# Generated by innovus_enablement/scripts/gen_fakeram.py: abstract 32x64 SRAM.
# Geometry is an assumption (see script header), not PDK data.
VERSION 5.8 ;
BUSBITCHARS "[]" ;
DIVIDERCHAR "/" ;

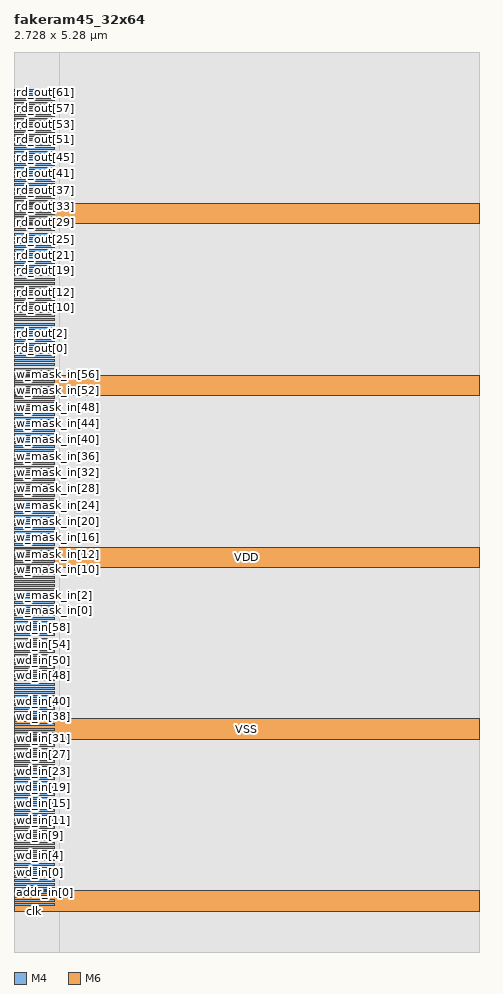
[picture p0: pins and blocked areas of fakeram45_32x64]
MACRO fakeram45_32x64
  CLASS BLOCK ;
  FOREIGN fakeram45_32x64 0 0 ;
  ORIGIN 0 0 ;
  SIZE 2.7280 BY 5.2800 ;
  SYMMETRY X Y R90 ;
  PIN clk
    DIRECTION INPUT ;
    USE CLOCK ;
    PORT
      LAYER M4 ;
        RECT 0 0.2700 0.2400 0.2820 ;
    END
  END clk
  PIN ce_in
    DIRECTION INPUT ;
    USE SIGNAL ;
    PORT
      LAYER M4 ;
        RECT 0 0.2940 0.2400 0.3060 ;
    END
  END ce_in
  PIN we_in
    DIRECTION INPUT ;
    USE SIGNAL ;
    PORT
      LAYER M4 ;
        RECT 0 0.3180 0.2400 0.3300 ;
    END
  END we_in
  PIN addr_in[0]
    DIRECTION INPUT ;
    USE SIGNAL ;
    PORT
      LAYER M4 ;
        RECT 0 0.3420 0.2400 0.3540 ;
    END
  END addr_in[0]
  PIN addr_in[1]
    DIRECTION INPUT ;
    USE SIGNAL ;
    PORT
      LAYER M4 ;
        RECT 0 0.3660 0.2400 0.3780 ;
    END
  END addr_in[1]
  PIN addr_in[2]
    DIRECTION INPUT ;
    USE SIGNAL ;
    PORT
      LAYER M4 ;
        RECT 0 0.3900 0.2400 0.4020 ;
    END
  END addr_in[2]
  PIN addr_in[3]
    DIRECTION INPUT ;
    USE SIGNAL ;
    PORT
      LAYER M4 ;
        RECT 0 0.4140 0.2400 0.4260 ;
    END
  END addr_in[3]
  PIN addr_in[4]
    DIRECTION INPUT ;
    USE SIGNAL ;
    PORT
      LAYER M4 ;
        RECT 0 0.4380 0.2400 0.4500 ;
    END
  END addr_in[4]
  PIN wd_in[0]
    DIRECTION INPUT ;
    USE SIGNAL ;
    PORT
      LAYER M4 ;
        RECT 0 0.4620 0.2400 0.4740 ;
    END
  END wd_in[0]
  PIN wd_in[1]
    DIRECTION INPUT ;
    USE SIGNAL ;
    PORT
      LAYER M4 ;
        RECT 0 0.4860 0.2400 0.4980 ;
    END
  END wd_in[1]
  PIN wd_in[2]
    DIRECTION INPUT ;
    USE SIGNAL ;
    PORT
      LAYER M4 ;
        RECT 0 0.5100 0.2400 0.5220 ;
    END
  END wd_in[2]
  PIN wd_in[3]
    DIRECTION INPUT ;
    USE SIGNAL ;
    PORT
      LAYER M4 ;
        RECT 0 0.5340 0.2400 0.5460 ;
    END
  END wd_in[3]
  PIN wd_in[4]
    DIRECTION INPUT ;
    USE SIGNAL ;
    PORT
      LAYER M4 ;
        RECT 0 0.5580 0.2400 0.5700 ;
    END
  END wd_in[4]
  PIN wd_in[5]
    DIRECTION INPUT ;
    USE SIGNAL ;
    PORT
      LAYER M4 ;
        RECT 0 0.5820 0.2400 0.5940 ;
    END
  END wd_in[5]
  PIN wd_in[6]
    DIRECTION INPUT ;
    USE SIGNAL ;
    PORT
      LAYER M4 ;
        RECT 0 0.6060 0.2400 0.6180 ;
    END
  END wd_in[6]
  PIN wd_in[7]
    DIRECTION INPUT ;
    USE SIGNAL ;
    PORT
      LAYER M4 ;
        RECT 0 0.6300 0.2400 0.6420 ;
    END
  END wd_in[7]
  PIN wd_in[8]
    DIRECTION INPUT ;
    USE SIGNAL ;
    PORT
      LAYER M4 ;
        RECT 0 0.6540 0.2400 0.6660 ;
    END
  END wd_in[8]
  PIN wd_in[9]
    DIRECTION INPUT ;
    USE SIGNAL ;
    PORT
      LAYER M4 ;
        RECT 0 0.6780 0.2400 0.6900 ;
    END
  END wd_in[9]
  PIN wd_in[10]
    DIRECTION INPUT ;
    USE SIGNAL ;
    PORT
      LAYER M4 ;
        RECT 0 0.7020 0.2400 0.7140 ;
    END
  END wd_in[10]
  PIN wd_in[11]
    DIRECTION INPUT ;
    USE SIGNAL ;
    PORT
      LAYER M4 ;
        RECT 0 0.7260 0.2400 0.7380 ;
    END
  END wd_in[11]
  PIN wd_in[12]
    DIRECTION INPUT ;
    USE SIGNAL ;
    PORT
      LAYER M4 ;
        RECT 0 0.7500 0.2400 0.7620 ;
    END
  END wd_in[12]
  PIN wd_in[13]
    DIRECTION INPUT ;
    USE SIGNAL ;
    PORT
      LAYER M4 ;
        RECT 0 0.7740 0.2400 0.7860 ;
    END
  END wd_in[13]
  PIN wd_in[14]
    DIRECTION INPUT ;
    USE SIGNAL ;
    PORT
      LAYER M4 ;
        RECT 0 0.7980 0.2400 0.8100 ;
    END
  END wd_in[14]
  PIN wd_in[15]
    DIRECTION INPUT ;
    USE SIGNAL ;
    PORT
      LAYER M4 ;
        RECT 0 0.8220 0.2400 0.8340 ;
    END
  END wd_in[15]
  PIN wd_in[16]
    DIRECTION INPUT ;
    USE SIGNAL ;
    PORT
      LAYER M4 ;
        RECT 0 0.8460 0.2400 0.8580 ;
    END
  END wd_in[16]
  PIN wd_in[17]
    DIRECTION INPUT ;
    USE SIGNAL ;
    PORT
      LAYER M4 ;
        RECT 0 0.8700 0.2400 0.8820 ;
    END
  END wd_in[17]
  PIN wd_in[18]
    DIRECTION INPUT ;
    USE SIGNAL ;
    PORT
      LAYER M4 ;
        RECT 0 0.8940 0.2400 0.9060 ;
    END
  END wd_in[18]
  PIN wd_in[19]
    DIRECTION INPUT ;
    USE SIGNAL ;
    PORT
      LAYER M4 ;
        RECT 0 0.9180 0.2400 0.9300 ;
    END
  END wd_in[19]
  PIN wd_in[20]
    DIRECTION INPUT ;
    USE SIGNAL ;
    PORT
      LAYER M4 ;
        RECT 0 0.9420 0.2400 0.9540 ;
    END
  END wd_in[20]
  PIN wd_in[21]
    DIRECTION INPUT ;
    USE SIGNAL ;
    PORT
      LAYER M4 ;
        RECT 0 0.9660 0.2400 0.9780 ;
    END
  END wd_in[21]
  PIN wd_in[22]
    DIRECTION INPUT ;
    USE SIGNAL ;
    PORT
      LAYER M4 ;
        RECT 0 0.9900 0.2400 1.0020 ;
    END
  END wd_in[22]
  PIN wd_in[23]
    DIRECTION INPUT ;
    USE SIGNAL ;
    PORT
      LAYER M4 ;
        RECT 0 1.0140 0.2400 1.0260 ;
    END
  END wd_in[23]
  PIN wd_in[24]
    DIRECTION INPUT ;
    USE SIGNAL ;
    PORT
      LAYER M4 ;
        RECT 0 1.0380 0.2400 1.0500 ;
    END
  END wd_in[24]
  PIN wd_in[25]
    DIRECTION INPUT ;
    USE SIGNAL ;
    PORT
      LAYER M4 ;
        RECT 0 1.0620 0.2400 1.0740 ;
    END
  END wd_in[25]
  PIN wd_in[26]
    DIRECTION INPUT ;
    USE SIGNAL ;
    PORT
      LAYER M4 ;
        RECT 0 1.0860 0.2400 1.0980 ;
    END
  END wd_in[26]
  PIN wd_in[27]
    DIRECTION INPUT ;
    USE SIGNAL ;
    PORT
      LAYER M4 ;
        RECT 0 1.1100 0.2400 1.1220 ;
    END
  END wd_in[27]
  PIN wd_in[28]
    DIRECTION INPUT ;
    USE SIGNAL ;
    PORT
      LAYER M4 ;
        RECT 0 1.1340 0.2400 1.1460 ;
    END
  END wd_in[28]
  PIN wd_in[29]
    DIRECTION INPUT ;
    USE SIGNAL ;
    PORT
      LAYER M4 ;
        RECT 0 1.1580 0.2400 1.1700 ;
    END
  END wd_in[29]
  PIN wd_in[30]
    DIRECTION INPUT ;
    USE SIGNAL ;
    PORT
      LAYER M4 ;
        RECT 0 1.1820 0.2400 1.1940 ;
    END
  END wd_in[30]
  PIN wd_in[31]
    DIRECTION INPUT ;
    USE SIGNAL ;
    PORT
      LAYER M4 ;
        RECT 0 1.2060 0.2400 1.2180 ;
    END
  END wd_in[31]
  PIN wd_in[32]
    DIRECTION INPUT ;
    USE SIGNAL ;
    PORT
      LAYER M4 ;
        RECT 0 1.2300 0.2400 1.2420 ;
    END
  END wd_in[32]
  PIN wd_in[33]
    DIRECTION INPUT ;
    USE SIGNAL ;
    PORT
      LAYER M4 ;
        RECT 0 1.2540 0.2400 1.2660 ;
    END
  END wd_in[33]
  PIN wd_in[34]
    DIRECTION INPUT ;
    USE SIGNAL ;
    PORT
      LAYER M4 ;
        RECT 0 1.2780 0.2400 1.2900 ;
    END
  END wd_in[34]
  PIN wd_in[35]
    DIRECTION INPUT ;
    USE SIGNAL ;
    PORT
      LAYER M4 ;
        RECT 0 1.3020 0.2400 1.3140 ;
    END
  END wd_in[35]
  PIN wd_in[36]
    DIRECTION INPUT ;
    USE SIGNAL ;
    PORT
      LAYER M4 ;
        RECT 0 1.3260 0.2400 1.3380 ;
    END
  END wd_in[36]
  PIN wd_in[37]
    DIRECTION INPUT ;
    USE SIGNAL ;
    PORT
      LAYER M4 ;
        RECT 0 1.3500 0.2400 1.3620 ;
    END
  END wd_in[37]
  PIN wd_in[38]
    DIRECTION INPUT ;
    USE SIGNAL ;
    PORT
      LAYER M4 ;
        RECT 0 1.3740 0.2400 1.3860 ;
    END
  END wd_in[38]
  PIN wd_in[39]
    DIRECTION INPUT ;
    USE SIGNAL ;
    PORT
      LAYER M4 ;
        RECT 0 1.3980 0.2400 1.4100 ;
    END
  END wd_in[39]
  PIN wd_in[40]
    DIRECTION INPUT ;
    USE SIGNAL ;
    PORT
      LAYER M4 ;
        RECT 0 1.4220 0.2400 1.4340 ;
    END
  END wd_in[40]
  PIN wd_in[41]
    DIRECTION INPUT ;
    USE SIGNAL ;
    PORT
      LAYER M4 ;
        RECT 0 1.4460 0.2400 1.4580 ;
    END
  END wd_in[41]
  PIN wd_in[42]
    DIRECTION INPUT ;
    USE SIGNAL ;
    PORT
      LAYER M4 ;
        RECT 0 1.4700 0.2400 1.4820 ;
    END
  END wd_in[42]
  PIN wd_in[43]
    DIRECTION INPUT ;
    USE SIGNAL ;
    PORT
      LAYER M4 ;
        RECT 0 1.4940 0.2400 1.5060 ;
    END
  END wd_in[43]
  PIN wd_in[44]
    DIRECTION INPUT ;
    USE SIGNAL ;
    PORT
      LAYER M4 ;
        RECT 0 1.5180 0.2400 1.5300 ;
    END
  END wd_in[44]
  PIN wd_in[45]
    DIRECTION INPUT ;
    USE SIGNAL ;
    PORT
      LAYER M4 ;
        RECT 0 1.5420 0.2400 1.5540 ;
    END
  END wd_in[45]
  PIN wd_in[46]
    DIRECTION INPUT ;
    USE SIGNAL ;
    PORT
      LAYER M4 ;
        RECT 0 1.5660 0.2400 1.5780 ;
    END
  END wd_in[46]
  PIN wd_in[47]
    DIRECTION INPUT ;
    USE SIGNAL ;
    PORT
      LAYER M4 ;
        RECT 0 1.5900 0.2400 1.6020 ;
    END
  END wd_in[47]
  PIN wd_in[48]
    DIRECTION INPUT ;
    USE SIGNAL ;
    PORT
      LAYER M4 ;
        RECT 0 1.6140 0.2400 1.6260 ;
    END
  END wd_in[48]
  PIN wd_in[49]
    DIRECTION INPUT ;
    USE SIGNAL ;
    PORT
      LAYER M4 ;
        RECT 0 1.6380 0.2400 1.6500 ;
    END
  END wd_in[49]
  PIN wd_in[50]
    DIRECTION INPUT ;
    USE SIGNAL ;
    PORT
      LAYER M4 ;
        RECT 0 1.6620 0.2400 1.6740 ;
    END
  END wd_in[50]
  PIN wd_in[51]
    DIRECTION INPUT ;
    USE SIGNAL ;
    PORT
      LAYER M4 ;
        RECT 0 1.6860 0.2400 1.6980 ;
    END
  END wd_in[51]
  PIN wd_in[52]
    DIRECTION INPUT ;
    USE SIGNAL ;
    PORT
      LAYER M4 ;
        RECT 0 1.7100 0.2400 1.7220 ;
    END
  END wd_in[52]
  PIN wd_in[53]
    DIRECTION INPUT ;
    USE SIGNAL ;
    PORT
      LAYER M4 ;
        RECT 0 1.7340 0.2400 1.7460 ;
    END
  END wd_in[53]
  PIN wd_in[54]
    DIRECTION INPUT ;
    USE SIGNAL ;
    PORT
      LAYER M4 ;
        RECT 0 1.7580 0.2400 1.7700 ;
    END
  END wd_in[54]
  PIN wd_in[55]
    DIRECTION INPUT ;
    USE SIGNAL ;
    PORT
      LAYER M4 ;
        RECT 0 1.7820 0.2400 1.7940 ;
    END
  END wd_in[55]
  PIN wd_in[56]
    DIRECTION INPUT ;
    USE SIGNAL ;
    PORT
      LAYER M4 ;
        RECT 0 1.8060 0.2400 1.8180 ;
    END
  END wd_in[56]
  PIN wd_in[57]
    DIRECTION INPUT ;
    USE SIGNAL ;
    PORT
      LAYER M4 ;
        RECT 0 1.8300 0.2400 1.8420 ;
    END
  END wd_in[57]
  PIN wd_in[58]
    DIRECTION INPUT ;
    USE SIGNAL ;
    PORT
      LAYER M4 ;
        RECT 0 1.8540 0.2400 1.8660 ;
    END
  END wd_in[58]
  PIN wd_in[59]
    DIRECTION INPUT ;
    USE SIGNAL ;
    PORT
      LAYER M4 ;
        RECT 0 1.8780 0.2400 1.8900 ;
    END
  END wd_in[59]
  PIN wd_in[60]
    DIRECTION INPUT ;
    USE SIGNAL ;
    PORT
      LAYER M4 ;
        RECT 0 1.9020 0.2400 1.9140 ;
    END
  END wd_in[60]
  PIN wd_in[61]
    DIRECTION INPUT ;
    USE SIGNAL ;
    PORT
      LAYER M4 ;
        RECT 0 1.9260 0.2400 1.9380 ;
    END
  END wd_in[61]
  PIN wd_in[62]
    DIRECTION INPUT ;
    USE SIGNAL ;
    PORT
      LAYER M4 ;
        RECT 0 1.9500 0.2400 1.9620 ;
    END
  END wd_in[62]
  PIN wd_in[63]
    DIRECTION INPUT ;
    USE SIGNAL ;
    PORT
      LAYER M4 ;
        RECT 0 1.9740 0.2400 1.9860 ;
    END
  END wd_in[63]
  PIN w_mask_in[0]
    DIRECTION INPUT ;
    USE SIGNAL ;
    PORT
      LAYER M4 ;
        RECT 0 1.9980 0.2400 2.0100 ;
    END
  END w_mask_in[0]
  PIN w_mask_in[1]
    DIRECTION INPUT ;
    USE SIGNAL ;
    PORT
      LAYER M4 ;
        RECT 0 2.0220 0.2400 2.0340 ;
    END
  END w_mask_in[1]
  PIN w_mask_in[2]
    DIRECTION INPUT ;
    USE SIGNAL ;
    PORT
      LAYER M4 ;
        RECT 0 2.0460 0.2400 2.0580 ;
    END
  END w_mask_in[2]
  PIN w_mask_in[3]
    DIRECTION INPUT ;
    USE SIGNAL ;
    PORT
      LAYER M4 ;
        RECT 0 2.0700 0.2400 2.0820 ;
    END
  END w_mask_in[3]
  PIN w_mask_in[4]
    DIRECTION INPUT ;
    USE SIGNAL ;
    PORT
      LAYER M4 ;
        RECT 0 2.0940 0.2400 2.1060 ;
    END
  END w_mask_in[4]
  PIN w_mask_in[5]
    DIRECTION INPUT ;
    USE SIGNAL ;
    PORT
      LAYER M4 ;
        RECT 0 2.1180 0.2400 2.1300 ;
    END
  END w_mask_in[5]
  PIN w_mask_in[6]
    DIRECTION INPUT ;
    USE SIGNAL ;
    PORT
      LAYER M4 ;
        RECT 0 2.1420 0.2400 2.1540 ;
    END
  END w_mask_in[6]
  PIN w_mask_in[7]
    DIRECTION INPUT ;
    USE SIGNAL ;
    PORT
      LAYER M4 ;
        RECT 0 2.1660 0.2400 2.1780 ;
    END
  END w_mask_in[7]
  PIN w_mask_in[8]
    DIRECTION INPUT ;
    USE SIGNAL ;
    PORT
      LAYER M4 ;
        RECT 0 2.1900 0.2400 2.2020 ;
    END
  END w_mask_in[8]
  PIN w_mask_in[9]
    DIRECTION INPUT ;
    USE SIGNAL ;
    PORT
      LAYER M4 ;
        RECT 0 2.2140 0.2400 2.2260 ;
    END
  END w_mask_in[9]
  PIN w_mask_in[10]
    DIRECTION INPUT ;
    USE SIGNAL ;
    PORT
      LAYER M4 ;
        RECT 0 2.2380 0.2400 2.2500 ;
    END
  END w_mask_in[10]
  PIN w_mask_in[11]
    DIRECTION INPUT ;
    USE SIGNAL ;
    PORT
      LAYER M4 ;
        RECT 0 2.2620 0.2400 2.2740 ;
    END
  END w_mask_in[11]
  PIN w_mask_in[12]
    DIRECTION INPUT ;
    USE SIGNAL ;
    PORT
      LAYER M4 ;
        RECT 0 2.2860 0.2400 2.2980 ;
    END
  END w_mask_in[12]
  PIN w_mask_in[13]
    DIRECTION INPUT ;
    USE SIGNAL ;
    PORT
      LAYER M4 ;
        RECT 0 2.3100 0.2400 2.3220 ;
    END
  END w_mask_in[13]
  PIN w_mask_in[14]
    DIRECTION INPUT ;
    USE SIGNAL ;
    PORT
      LAYER M4 ;
        RECT 0 2.3340 0.2400 2.3460 ;
    END
  END w_mask_in[14]
  PIN w_mask_in[15]
    DIRECTION INPUT ;
    USE SIGNAL ;
    PORT
      LAYER M4 ;
        RECT 0 2.3580 0.2400 2.3700 ;
    END
  END w_mask_in[15]
  PIN w_mask_in[16]
    DIRECTION INPUT ;
    USE SIGNAL ;
    PORT
      LAYER M4 ;
        RECT 0 2.3820 0.2400 2.3940 ;
    END
  END w_mask_in[16]
  PIN w_mask_in[17]
    DIRECTION INPUT ;
    USE SIGNAL ;
    PORT
      LAYER M4 ;
        RECT 0 2.4060 0.2400 2.4180 ;
    END
  END w_mask_in[17]
  PIN w_mask_in[18]
    DIRECTION INPUT ;
    USE SIGNAL ;
    PORT
      LAYER M4 ;
        RECT 0 2.4300 0.2400 2.4420 ;
    END
  END w_mask_in[18]
  PIN w_mask_in[19]
    DIRECTION INPUT ;
    USE SIGNAL ;
    PORT
      LAYER M4 ;
        RECT 0 2.4540 0.2400 2.4660 ;
    END
  END w_mask_in[19]
  PIN w_mask_in[20]
    DIRECTION INPUT ;
    USE SIGNAL ;
    PORT
      LAYER M4 ;
        RECT 0 2.4780 0.2400 2.4900 ;
    END
  END w_mask_in[20]
  PIN w_mask_in[21]
    DIRECTION INPUT ;
    USE SIGNAL ;
    PORT
      LAYER M4 ;
        RECT 0 2.5020 0.2400 2.5140 ;
    END
  END w_mask_in[21]
  PIN w_mask_in[22]
    DIRECTION INPUT ;
    USE SIGNAL ;
    PORT
      LAYER M4 ;
        RECT 0 2.5260 0.2400 2.5380 ;
    END
  END w_mask_in[22]
  PIN w_mask_in[23]
    DIRECTION INPUT ;
    USE SIGNAL ;
    PORT
      LAYER M4 ;
        RECT 0 2.5500 0.2400 2.5620 ;
    END
  END w_mask_in[23]
  PIN w_mask_in[24]
    DIRECTION INPUT ;
    USE SIGNAL ;
    PORT
      LAYER M4 ;
        RECT 0 2.5740 0.2400 2.5860 ;
    END
  END w_mask_in[24]
  PIN w_mask_in[25]
    DIRECTION INPUT ;
    USE SIGNAL ;
    PORT
      LAYER M4 ;
        RECT 0 2.5980 0.2400 2.6100 ;
    END
  END w_mask_in[25]
  PIN w_mask_in[26]
    DIRECTION INPUT ;
    USE SIGNAL ;
    PORT
      LAYER M4 ;
        RECT 0 2.6220 0.2400 2.6340 ;
    END
  END w_mask_in[26]
  PIN w_mask_in[27]
    DIRECTION INPUT ;
    USE SIGNAL ;
    PORT
      LAYER M4 ;
        RECT 0 2.6460 0.2400 2.6580 ;
    END
  END w_mask_in[27]
  PIN w_mask_in[28]
    DIRECTION INPUT ;
    USE SIGNAL ;
    PORT
      LAYER M4 ;
        RECT 0 2.6700 0.2400 2.6820 ;
    END
  END w_mask_in[28]
  PIN w_mask_in[29]
    DIRECTION INPUT ;
    USE SIGNAL ;
    PORT
      LAYER M4 ;
        RECT 0 2.6940 0.2400 2.7060 ;
    END
  END w_mask_in[29]
  PIN w_mask_in[30]
    DIRECTION INPUT ;
    USE SIGNAL ;
    PORT
      LAYER M4 ;
        RECT 0 2.7180 0.2400 2.7300 ;
    END
  END w_mask_in[30]
  PIN w_mask_in[31]
    DIRECTION INPUT ;
    USE SIGNAL ;
    PORT
      LAYER M4 ;
        RECT 0 2.7420 0.2400 2.7540 ;
    END
  END w_mask_in[31]
  PIN w_mask_in[32]
    DIRECTION INPUT ;
    USE SIGNAL ;
    PORT
      LAYER M4 ;
        RECT 0 2.7660 0.2400 2.7780 ;
    END
  END w_mask_in[32]
  PIN w_mask_in[33]
    DIRECTION INPUT ;
    USE SIGNAL ;
    PORT
      LAYER M4 ;
        RECT 0 2.7900 0.2400 2.8020 ;
    END
  END w_mask_in[33]
  PIN w_mask_in[34]
    DIRECTION INPUT ;
    USE SIGNAL ;
    PORT
      LAYER M4 ;
        RECT 0 2.8140 0.2400 2.8260 ;
    END
  END w_mask_in[34]
  PIN w_mask_in[35]
    DIRECTION INPUT ;
    USE SIGNAL ;
    PORT
      LAYER M4 ;
        RECT 0 2.8380 0.2400 2.8500 ;
    END
  END w_mask_in[35]
  PIN w_mask_in[36]
    DIRECTION INPUT ;
    USE SIGNAL ;
    PORT
      LAYER M4 ;
        RECT 0 2.8620 0.2400 2.8740 ;
    END
  END w_mask_in[36]
  PIN w_mask_in[37]
    DIRECTION INPUT ;
    USE SIGNAL ;
    PORT
      LAYER M4 ;
        RECT 0 2.8860 0.2400 2.8980 ;
    END
  END w_mask_in[37]
  PIN w_mask_in[38]
    DIRECTION INPUT ;
    USE SIGNAL ;
    PORT
      LAYER M4 ;
        RECT 0 2.9100 0.2400 2.9220 ;
    END
  END w_mask_in[38]
  PIN w_mask_in[39]
    DIRECTION INPUT ;
    USE SIGNAL ;
    PORT
      LAYER M4 ;
        RECT 0 2.9340 0.2400 2.9460 ;
    END
  END w_mask_in[39]
  PIN w_mask_in[40]
    DIRECTION INPUT ;
    USE SIGNAL ;
    PORT
      LAYER M4 ;
        RECT 0 2.9580 0.2400 2.9700 ;
    END
  END w_mask_in[40]
  PIN w_mask_in[41]
    DIRECTION INPUT ;
    USE SIGNAL ;
    PORT
      LAYER M4 ;
        RECT 0 2.9820 0.2400 2.9940 ;
    END
  END w_mask_in[41]
  PIN w_mask_in[42]
    DIRECTION INPUT ;
    USE SIGNAL ;
    PORT
      LAYER M4 ;
        RECT 0 3.0060 0.2400 3.0180 ;
    END
  END w_mask_in[42]
  PIN w_mask_in[43]
    DIRECTION INPUT ;
    USE SIGNAL ;
    PORT
      LAYER M4 ;
        RECT 0 3.0300 0.2400 3.0420 ;
    END
  END w_mask_in[43]
  PIN w_mask_in[44]
    DIRECTION INPUT ;
    USE SIGNAL ;
    PORT
      LAYER M4 ;
        RECT 0 3.0540 0.2400 3.0660 ;
    END
  END w_mask_in[44]
  PIN w_mask_in[45]
    DIRECTION INPUT ;
    USE SIGNAL ;
    PORT
      LAYER M4 ;
        RECT 0 3.0780 0.2400 3.0900 ;
    END
  END w_mask_in[45]
  PIN w_mask_in[46]
    DIRECTION INPUT ;
    USE SIGNAL ;
    PORT
      LAYER M4 ;
        RECT 0 3.1020 0.2400 3.1140 ;
    END
  END w_mask_in[46]
  PIN w_mask_in[47]
    DIRECTION INPUT ;
    USE SIGNAL ;
    PORT
      LAYER M4 ;
        RECT 0 3.1260 0.2400 3.1380 ;
    END
  END w_mask_in[47]
  PIN w_mask_in[48]
    DIRECTION INPUT ;
    USE SIGNAL ;
    PORT
      LAYER M4 ;
        RECT 0 3.1500 0.2400 3.1620 ;
    END
  END w_mask_in[48]
  PIN w_mask_in[49]
    DIRECTION INPUT ;
    USE SIGNAL ;
    PORT
      LAYER M4 ;
        RECT 0 3.1740 0.2400 3.1860 ;
    END
  END w_mask_in[49]
  PIN w_mask_in[50]
    DIRECTION INPUT ;
    USE SIGNAL ;
    PORT
      LAYER M4 ;
        RECT 0 3.1980 0.2400 3.2100 ;
    END
  END w_mask_in[50]
  PIN w_mask_in[51]
    DIRECTION INPUT ;
    USE SIGNAL ;
    PORT
      LAYER M4 ;
        RECT 0 3.2220 0.2400 3.2340 ;
    END
  END w_mask_in[51]
  PIN w_mask_in[52]
    DIRECTION INPUT ;
    USE SIGNAL ;
    PORT
      LAYER M4 ;
        RECT 0 3.2460 0.2400 3.2580 ;
    END
  END w_mask_in[52]
  PIN w_mask_in[53]
    DIRECTION INPUT ;
    USE SIGNAL ;
    PORT
      LAYER M4 ;
        RECT 0 3.2700 0.2400 3.2820 ;
    END
  END w_mask_in[53]
  PIN w_mask_in[54]
    DIRECTION INPUT ;
    USE SIGNAL ;
    PORT
      LAYER M4 ;
        RECT 0 3.2940 0.2400 3.3060 ;
    END
  END w_mask_in[54]
  PIN w_mask_in[55]
    DIRECTION INPUT ;
    USE SIGNAL ;
    PORT
      LAYER M4 ;
        RECT 0 3.3180 0.2400 3.3300 ;
    END
  END w_mask_in[55]
  PIN w_mask_in[56]
    DIRECTION INPUT ;
    USE SIGNAL ;
    PORT
      LAYER M4 ;
        RECT 0 3.3420 0.2400 3.3540 ;
    END
  END w_mask_in[56]
  PIN w_mask_in[57]
    DIRECTION INPUT ;
    USE SIGNAL ;
    PORT
      LAYER M4 ;
        RECT 0 3.3660 0.2400 3.3780 ;
    END
  END w_mask_in[57]
  PIN w_mask_in[58]
    DIRECTION INPUT ;
    USE SIGNAL ;
    PORT
      LAYER M4 ;
        RECT 0 3.3900 0.2400 3.4020 ;
    END
  END w_mask_in[58]
  PIN w_mask_in[59]
    DIRECTION INPUT ;
    USE SIGNAL ;
    PORT
      LAYER M4 ;
        RECT 0 3.4140 0.2400 3.4260 ;
    END
  END w_mask_in[59]
  PIN w_mask_in[60]
    DIRECTION INPUT ;
    USE SIGNAL ;
    PORT
      LAYER M4 ;
        RECT 0 3.4380 0.2400 3.4500 ;
    END
  END w_mask_in[60]
  PIN w_mask_in[61]
    DIRECTION INPUT ;
    USE SIGNAL ;
    PORT
      LAYER M4 ;
        RECT 0 3.4620 0.2400 3.4740 ;
    END
  END w_mask_in[61]
  PIN w_mask_in[62]
    DIRECTION INPUT ;
    USE SIGNAL ;
    PORT
      LAYER M4 ;
        RECT 0 3.4860 0.2400 3.4980 ;
    END
  END w_mask_in[62]
  PIN w_mask_in[63]
    DIRECTION INPUT ;
    USE SIGNAL ;
    PORT
      LAYER M4 ;
        RECT 0 3.5100 0.2400 3.5220 ;
    END
  END w_mask_in[63]
  PIN rd_out[0]
    DIRECTION OUTPUT ;
    USE SIGNAL ;
    PORT
      LAYER M4 ;
        RECT 0 3.5340 0.2400 3.5460 ;
    END
  END rd_out[0]
  PIN rd_out[1]
    DIRECTION OUTPUT ;
    USE SIGNAL ;
    PORT
      LAYER M4 ;
        RECT 0 3.5580 0.2400 3.5700 ;
    END
  END rd_out[1]
  PIN rd_out[2]
    DIRECTION OUTPUT ;
    USE SIGNAL ;
    PORT
      LAYER M4 ;
        RECT 0 3.5820 0.2400 3.5940 ;
    END
  END rd_out[2]
  PIN rd_out[3]
    DIRECTION OUTPUT ;
    USE SIGNAL ;
    PORT
      LAYER M4 ;
        RECT 0 3.6060 0.2400 3.6180 ;
    END
  END rd_out[3]
  PIN rd_out[4]
    DIRECTION OUTPUT ;
    USE SIGNAL ;
    PORT
      LAYER M4 ;
        RECT 0 3.6300 0.2400 3.6420 ;
    END
  END rd_out[4]
  PIN rd_out[5]
    DIRECTION OUTPUT ;
    USE SIGNAL ;
    PORT
      LAYER M4 ;
        RECT 0 3.6540 0.2400 3.6660 ;
    END
  END rd_out[5]
  PIN rd_out[6]
    DIRECTION OUTPUT ;
    USE SIGNAL ;
    PORT
      LAYER M4 ;
        RECT 0 3.6780 0.2400 3.6900 ;
    END
  END rd_out[6]
  PIN rd_out[7]
    DIRECTION OUTPUT ;
    USE SIGNAL ;
    PORT
      LAYER M4 ;
        RECT 0 3.7020 0.2400 3.7140 ;
    END
  END rd_out[7]
  PIN rd_out[8]
    DIRECTION OUTPUT ;
    USE SIGNAL ;
    PORT
      LAYER M4 ;
        RECT 0 3.7260 0.2400 3.7380 ;
    END
  END rd_out[8]
  PIN rd_out[9]
    DIRECTION OUTPUT ;
    USE SIGNAL ;
    PORT
      LAYER M4 ;
        RECT 0 3.7500 0.2400 3.7620 ;
    END
  END rd_out[9]
  PIN rd_out[10]
    DIRECTION OUTPUT ;
    USE SIGNAL ;
    PORT
      LAYER M4 ;
        RECT 0 3.7740 0.2400 3.7860 ;
    END
  END rd_out[10]
  PIN rd_out[11]
    DIRECTION OUTPUT ;
    USE SIGNAL ;
    PORT
      LAYER M4 ;
        RECT 0 3.7980 0.2400 3.8100 ;
    END
  END rd_out[11]
  PIN rd_out[12]
    DIRECTION OUTPUT ;
    USE SIGNAL ;
    PORT
      LAYER M4 ;
        RECT 0 3.8220 0.2400 3.8340 ;
    END
  END rd_out[12]
  PIN rd_out[13]
    DIRECTION OUTPUT ;
    USE SIGNAL ;
    PORT
      LAYER M4 ;
        RECT 0 3.8460 0.2400 3.8580 ;
    END
  END rd_out[13]
  PIN rd_out[14]
    DIRECTION OUTPUT ;
    USE SIGNAL ;
    PORT
      LAYER M4 ;
        RECT 0 3.8700 0.2400 3.8820 ;
    END
  END rd_out[14]
  PIN rd_out[15]
    DIRECTION OUTPUT ;
    USE SIGNAL ;
    PORT
      LAYER M4 ;
        RECT 0 3.8940 0.2400 3.9060 ;
    END
  END rd_out[15]
  PIN rd_out[16]
    DIRECTION OUTPUT ;
    USE SIGNAL ;
    PORT
      LAYER M4 ;
        RECT 0 3.9180 0.2400 3.9300 ;
    END
  END rd_out[16]
  PIN rd_out[17]
    DIRECTION OUTPUT ;
    USE SIGNAL ;
    PORT
      LAYER M4 ;
        RECT 0 3.9420 0.2400 3.9540 ;
    END
  END rd_out[17]
  PIN rd_out[18]
    DIRECTION OUTPUT ;
    USE SIGNAL ;
    PORT
      LAYER M4 ;
        RECT 0 3.9660 0.2400 3.9780 ;
    END
  END rd_out[18]
  PIN rd_out[19]
    DIRECTION OUTPUT ;
    USE SIGNAL ;
    PORT
      LAYER M4 ;
        RECT 0 3.9900 0.2400 4.0020 ;
    END
  END rd_out[19]
  PIN rd_out[20]
    DIRECTION OUTPUT ;
    USE SIGNAL ;
    PORT
      LAYER M4 ;
        RECT 0 4.0140 0.2400 4.0260 ;
    END
  END rd_out[20]
  PIN rd_out[21]
    DIRECTION OUTPUT ;
    USE SIGNAL ;
    PORT
      LAYER M4 ;
        RECT 0 4.0380 0.2400 4.0500 ;
    END
  END rd_out[21]
  PIN rd_out[22]
    DIRECTION OUTPUT ;
    USE SIGNAL ;
    PORT
      LAYER M4 ;
        RECT 0 4.0620 0.2400 4.0740 ;
    END
  END rd_out[22]
  PIN rd_out[23]
    DIRECTION OUTPUT ;
    USE SIGNAL ;
    PORT
      LAYER M4 ;
        RECT 0 4.0860 0.2400 4.0980 ;
    END
  END rd_out[23]
  PIN rd_out[24]
    DIRECTION OUTPUT ;
    USE SIGNAL ;
    PORT
      LAYER M4 ;
        RECT 0 4.1100 0.2400 4.1220 ;
    END
  END rd_out[24]
  PIN rd_out[25]
    DIRECTION OUTPUT ;
    USE SIGNAL ;
    PORT
      LAYER M4 ;
        RECT 0 4.1340 0.2400 4.1460 ;
    END
  END rd_out[25]
  PIN rd_out[26]
    DIRECTION OUTPUT ;
    USE SIGNAL ;
    PORT
      LAYER M4 ;
        RECT 0 4.1580 0.2400 4.1700 ;
    END
  END rd_out[26]
  PIN rd_out[27]
    DIRECTION OUTPUT ;
    USE SIGNAL ;
    PORT
      LAYER M4 ;
        RECT 0 4.1820 0.2400 4.1940 ;
    END
  END rd_out[27]
  PIN rd_out[28]
    DIRECTION OUTPUT ;
    USE SIGNAL ;
    PORT
      LAYER M4 ;
        RECT 0 4.2060 0.2400 4.2180 ;
    END
  END rd_out[28]
  PIN rd_out[29]
    DIRECTION OUTPUT ;
    USE SIGNAL ;
    PORT
      LAYER M4 ;
        RECT 0 4.2300 0.2400 4.2420 ;
    END
  END rd_out[29]
  PIN rd_out[30]
    DIRECTION OUTPUT ;
    USE SIGNAL ;
    PORT
      LAYER M4 ;
        RECT 0 4.2540 0.2400 4.2660 ;
    END
  END rd_out[30]
  PIN rd_out[31]
    DIRECTION OUTPUT ;
    USE SIGNAL ;
    PORT
      LAYER M4 ;
        RECT 0 4.2780 0.2400 4.2900 ;
    END
  END rd_out[31]
  PIN rd_out[32]
    DIRECTION OUTPUT ;
    USE SIGNAL ;
    PORT
      LAYER M4 ;
        RECT 0 4.3020 0.2400 4.3140 ;
    END
  END rd_out[32]
  PIN rd_out[33]
    DIRECTION OUTPUT ;
    USE SIGNAL ;
    PORT
      LAYER M4 ;
        RECT 0 4.3260 0.2400 4.3380 ;
    END
  END rd_out[33]
  PIN rd_out[34]
    DIRECTION OUTPUT ;
    USE SIGNAL ;
    PORT
      LAYER M4 ;
        RECT 0 4.3500 0.2400 4.3620 ;
    END
  END rd_out[34]
  PIN rd_out[35]
    DIRECTION OUTPUT ;
    USE SIGNAL ;
    PORT
      LAYER M4 ;
        RECT 0 4.3740 0.2400 4.3860 ;
    END
  END rd_out[35]
  PIN rd_out[36]
    DIRECTION OUTPUT ;
    USE SIGNAL ;
    PORT
      LAYER M4 ;
        RECT 0 4.3980 0.2400 4.4100 ;
    END
  END rd_out[36]
  PIN rd_out[37]
    DIRECTION OUTPUT ;
    USE SIGNAL ;
    PORT
      LAYER M4 ;
        RECT 0 4.4220 0.2400 4.4340 ;
    END
  END rd_out[37]
  PIN rd_out[38]
    DIRECTION OUTPUT ;
    USE SIGNAL ;
    PORT
      LAYER M4 ;
        RECT 0 4.4460 0.2400 4.4580 ;
    END
  END rd_out[38]
  PIN rd_out[39]
    DIRECTION OUTPUT ;
    USE SIGNAL ;
    PORT
      LAYER M4 ;
        RECT 0 4.4700 0.2400 4.4820 ;
    END
  END rd_out[39]
  PIN rd_out[40]
    DIRECTION OUTPUT ;
    USE SIGNAL ;
    PORT
      LAYER M4 ;
        RECT 0 4.4940 0.2400 4.5060 ;
    END
  END rd_out[40]
  PIN rd_out[41]
    DIRECTION OUTPUT ;
    USE SIGNAL ;
    PORT
      LAYER M4 ;
        RECT 0 4.5180 0.2400 4.5300 ;
    END
  END rd_out[41]
  PIN rd_out[42]
    DIRECTION OUTPUT ;
    USE SIGNAL ;
    PORT
      LAYER M4 ;
        RECT 0 4.5420 0.2400 4.5540 ;
    END
  END rd_out[42]
  PIN rd_out[43]
    DIRECTION OUTPUT ;
    USE SIGNAL ;
    PORT
      LAYER M4 ;
        RECT 0 4.5660 0.2400 4.5780 ;
    END
  END rd_out[43]
  PIN rd_out[44]
    DIRECTION OUTPUT ;
    USE SIGNAL ;
    PORT
      LAYER M4 ;
        RECT 0 4.5900 0.2400 4.6020 ;
    END
  END rd_out[44]
  PIN rd_out[45]
    DIRECTION OUTPUT ;
    USE SIGNAL ;
    PORT
      LAYER M4 ;
        RECT 0 4.6140 0.2400 4.6260 ;
    END
  END rd_out[45]
  PIN rd_out[46]
    DIRECTION OUTPUT ;
    USE SIGNAL ;
    PORT
      LAYER M4 ;
        RECT 0 4.6380 0.2400 4.6500 ;
    END
  END rd_out[46]
  PIN rd_out[47]
    DIRECTION OUTPUT ;
    USE SIGNAL ;
    PORT
      LAYER M4 ;
        RECT 0 4.6620 0.2400 4.6740 ;
    END
  END rd_out[47]
  PIN rd_out[48]
    DIRECTION OUTPUT ;
    USE SIGNAL ;
    PORT
      LAYER M4 ;
        RECT 0 4.6860 0.2400 4.6980 ;
    END
  END rd_out[48]
  PIN rd_out[49]
    DIRECTION OUTPUT ;
    USE SIGNAL ;
    PORT
      LAYER M4 ;
        RECT 0 4.7100 0.2400 4.7220 ;
    END
  END rd_out[49]
  PIN rd_out[50]
    DIRECTION OUTPUT ;
    USE SIGNAL ;
    PORT
      LAYER M4 ;
        RECT 0 4.7340 0.2400 4.7460 ;
    END
  END rd_out[50]
  PIN rd_out[51]
    DIRECTION OUTPUT ;
    USE SIGNAL ;
    PORT
      LAYER M4 ;
        RECT 0 4.7580 0.2400 4.7700 ;
    END
  END rd_out[51]
  PIN rd_out[52]
    DIRECTION OUTPUT ;
    USE SIGNAL ;
    PORT
      LAYER M4 ;
        RECT 0 4.7820 0.2400 4.7940 ;
    END
  END rd_out[52]
  PIN rd_out[53]
    DIRECTION OUTPUT ;
    USE SIGNAL ;
    PORT
      LAYER M4 ;
        RECT 0 4.8060 0.2400 4.8180 ;
    END
  END rd_out[53]
  PIN rd_out[54]
    DIRECTION OUTPUT ;
    USE SIGNAL ;
    PORT
      LAYER M4 ;
        RECT 0 4.8300 0.2400 4.8420 ;
    END
  END rd_out[54]
  PIN rd_out[55]
    DIRECTION OUTPUT ;
    USE SIGNAL ;
    PORT
      LAYER M4 ;
        RECT 0 4.8540 0.2400 4.8660 ;
    END
  END rd_out[55]
  PIN rd_out[56]
    DIRECTION OUTPUT ;
    USE SIGNAL ;
    PORT
      LAYER M4 ;
        RECT 0 4.8780 0.2400 4.8900 ;
    END
  END rd_out[56]
  PIN rd_out[57]
    DIRECTION OUTPUT ;
    USE SIGNAL ;
    PORT
      LAYER M4 ;
        RECT 0 4.9020 0.2400 4.9140 ;
    END
  END rd_out[57]
  PIN rd_out[58]
    DIRECTION OUTPUT ;
    USE SIGNAL ;
    PORT
      LAYER M4 ;
        RECT 0 4.9260 0.2400 4.9380 ;
    END
  END rd_out[58]
  PIN rd_out[59]
    DIRECTION OUTPUT ;
    USE SIGNAL ;
    PORT
      LAYER M4 ;
        RECT 0 4.9500 0.2400 4.9620 ;
    END
  END rd_out[59]
  PIN rd_out[60]
    DIRECTION OUTPUT ;
    USE SIGNAL ;
    PORT
      LAYER M4 ;
        RECT 0 4.9740 0.2400 4.9860 ;
    END
  END rd_out[60]
  PIN rd_out[61]
    DIRECTION OUTPUT ;
    USE SIGNAL ;
    PORT
      LAYER M4 ;
        RECT 0 4.9980 0.2400 5.0100 ;
    END
  END rd_out[61]
  PIN rd_out[62]
    DIRECTION OUTPUT ;
    USE SIGNAL ;
    PORT
      LAYER M4 ;
        RECT 0 5.0220 0.2400 5.0340 ;
    END
  END rd_out[62]
  PIN rd_out[63]
    DIRECTION OUTPUT ;
    USE SIGNAL ;
    PORT
      LAYER M4 ;
        RECT 0 5.0460 0.2400 5.0580 ;
    END
  END rd_out[63]
  PIN VDD
    DIRECTION INOUT ;
    USE POWER ;
    PORT
      LAYER M6 ;
        RECT 0 0.2400 2.7280 0.3600 ;
        RECT 0 2.2560 2.7280 2.3760 ;
        RECT 0 4.2720 2.7280 4.3920 ;
    END
  END VDD
  PIN VSS
    DIRECTION INOUT ;
    USE GROUND ;
    PORT
      LAYER M6 ;
        RECT 0 1.2480 2.7280 1.3680 ;
        RECT 0 3.2640 2.7280 3.3840 ;
    END
  END VSS
  OBS
    LAYER M0 ;
      RECT 0 0 2.7280 5.2800 ;
    LAYER M1 ;
      RECT 0 0 2.7280 5.2800 ;
    LAYER M2 ;
      RECT 0 0 2.7280 5.2800 ;
    LAYER M3 ;
      RECT 0 0 2.7280 5.2800 ;
    LAYER VIA0 ;
      RECT 0 0 2.7280 5.2800 ;
    LAYER VIA1 ;
      RECT 0 0 2.7280 5.2800 ;
    LAYER VIA2 ;
      RECT 0 0 2.7280 5.2800 ;
    LAYER VIA3 ;
      RECT 0 0 2.7280 5.2800 ;
    LAYER M4 ;
      RECT 0.2640 0 2.7280 5.2800 ;
  END
END fakeram45_32x64

END LIBRARY
